VERSION 5.7 ;
  NOWIREEXTENSIONATPIN ON ;
  DIVIDERCHAR "/" ;
  BUSBITCHARS "[]" ;
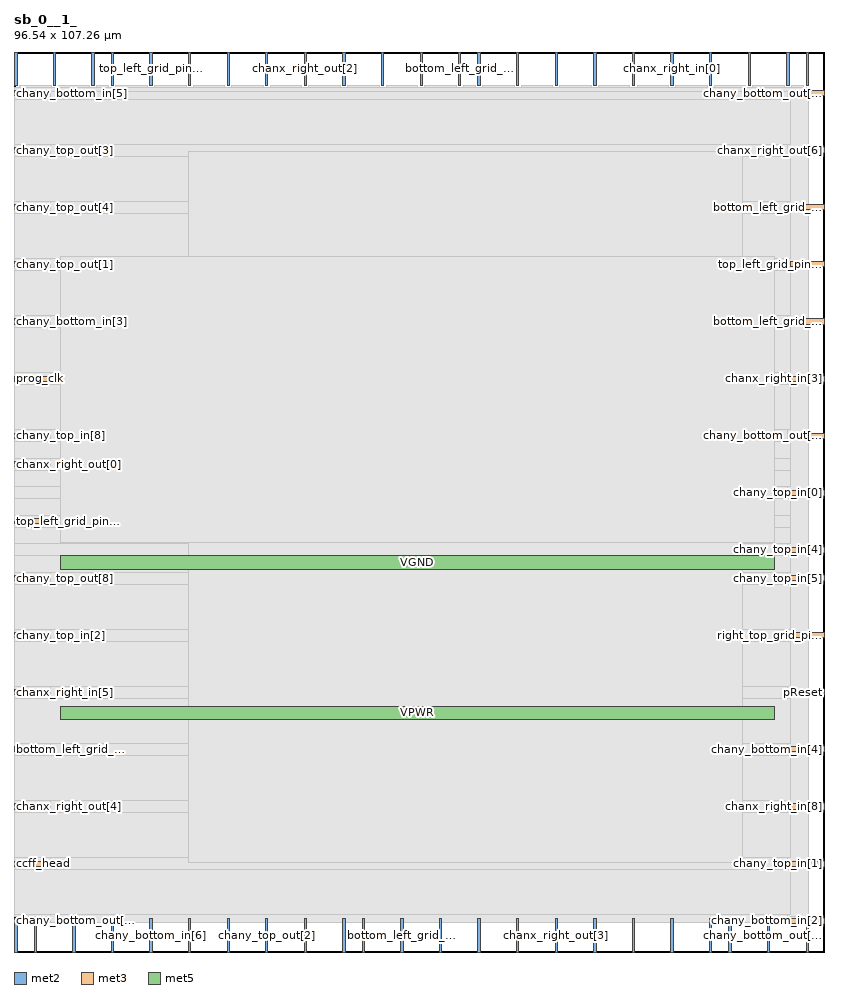
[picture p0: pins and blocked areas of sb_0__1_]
MACRO sb_0__1_
  CLASS BLOCK ;
  FOREIGN sb_0__1_ ;
  ORIGIN 0.000 0.000 ;
  SIZE 96.540 BY 107.260 ;
  PIN bottom_left_grid_pin_11_
    DIRECTION INPUT ;
    PORT
      LAYER met2 ;
        RECT 52.990 103.260 53.270 107.260 ;
    END
  END bottom_left_grid_pin_11_
  PIN bottom_left_grid_pin_13_
    DIRECTION INPUT ;
    PORT
      LAYER met2 ;
        RECT 92.090 103.260 92.370 107.260 ;
    END
  END bottom_left_grid_pin_13_
  PIN bottom_left_grid_pin_15_
    DIRECTION INPUT ;
    PORT
      LAYER met3 ;
        RECT 0.000 23.840 4.000 24.440 ;
    END
  END bottom_left_grid_pin_15_
  PIN bottom_left_grid_pin_1_
    DIRECTION INPUT ;
    PORT
      LAYER met2 ;
        RECT 9.290 103.260 9.570 107.260 ;
    END
  END bottom_left_grid_pin_1_
  PIN bottom_left_grid_pin_3_
    DIRECTION INPUT ;
    PORT
      LAYER met3 ;
        RECT 92.540 74.840 96.540 75.440 ;
    END
  END bottom_left_grid_pin_3_
  PIN bottom_left_grid_pin_5_
    DIRECTION INPUT ;
    PORT
      LAYER met2 ;
        RECT 39.190 0.000 39.470 4.000 ;
    END
  END bottom_left_grid_pin_5_
  PIN bottom_left_grid_pin_7_
    DIRECTION INPUT ;
    PORT
      LAYER met2 ;
        RECT 46.090 0.000 46.370 4.000 ;
    END
  END bottom_left_grid_pin_7_
  PIN bottom_left_grid_pin_9_
    DIRECTION INPUT ;
    PORT
      LAYER met3 ;
        RECT 92.540 88.440 96.540 89.040 ;
    END
  END bottom_left_grid_pin_9_
  PIN bottom_right_grid_pin_11_
    DIRECTION INPUT ;
    PORT
      LAYER met2 ;
        RECT 55.290 103.260 55.570 107.260 ;
    END
  END bottom_right_grid_pin_11_
  PIN ccff_head
    DIRECTION INPUT ;
    PORT
      LAYER met3 ;
        RECT 0.000 10.240 4.000 10.840 ;
    END
  END ccff_head
  PIN ccff_tail
    DIRECTION OUTPUT TRISTATE ;
    PORT
      LAYER met2 ;
        RECT 94.390 0.000 94.670 4.000 ;
    END
  END ccff_tail
  PIN chanx_right_in[0]
    DIRECTION INPUT ;
    PORT
      LAYER met2 ;
        RECT 78.290 103.260 78.570 107.260 ;
    END
  END chanx_right_in[0]
  PIN chanx_right_in[1]
    DIRECTION INPUT ;
    PORT
      LAYER met2 ;
        RECT 50.690 0.000 50.970 4.000 ;
    END
  END chanx_right_in[1]
  PIN chanx_right_in[2]
    DIRECTION INPUT ;
    PORT
      LAYER met2 ;
        RECT 29.990 103.260 30.270 107.260 ;
    END
  END chanx_right_in[2]
  PIN chanx_right_in[3]
    DIRECTION INPUT ;
    PORT
      LAYER met3 ;
        RECT 92.540 68.040 96.540 68.640 ;
    END
  END chanx_right_in[3]
  PIN chanx_right_in[4]
    DIRECTION INPUT ;
    PORT
      LAYER met2 ;
        RECT 6.990 0.000 7.270 4.000 ;
    END
  END chanx_right_in[4]
  PIN chanx_right_in[5]
    DIRECTION INPUT ;
    PORT
      LAYER met3 ;
        RECT 0.000 30.640 4.000 31.240 ;
    END
  END chanx_right_in[5]
  PIN chanx_right_in[6]
    DIRECTION INPUT ;
    PORT
      LAYER met2 ;
        RECT 59.890 103.260 60.170 107.260 ;
    END
  END chanx_right_in[6]
  PIN chanx_right_in[7]
    DIRECTION INPUT ;
    PORT
      LAYER met2 ;
        RECT 82.890 0.000 83.170 4.000 ;
    END
  END chanx_right_in[7]
  PIN chanx_right_in[8]
    DIRECTION INPUT ;
    PORT
      LAYER met3 ;
        RECT 92.540 17.040 96.540 17.640 ;
    END
  END chanx_right_in[8]
  PIN chanx_right_out[0]
    DIRECTION OUTPUT TRISTATE ;
    PORT
      LAYER met3 ;
        RECT 0.000 57.840 4.000 58.440 ;
    END
  END chanx_right_out[0]
  PIN chanx_right_out[1]
    DIRECTION OUTPUT TRISTATE ;
    PORT
      LAYER met2 ;
        RECT 94.390 103.260 94.670 107.260 ;
    END
  END chanx_right_out[1]
  PIN chanx_right_out[2]
    DIRECTION OUTPUT TRISTATE ;
    PORT
      LAYER met2 ;
        RECT 34.590 103.260 34.870 107.260 ;
    END
  END chanx_right_out[2]
  PIN chanx_right_out[3]
    DIRECTION OUTPUT TRISTATE ;
    PORT
      LAYER met2 ;
        RECT 64.490 0.000 64.770 4.000 ;
    END
  END chanx_right_out[3]
  PIN chanx_right_out[4]
    DIRECTION OUTPUT TRISTATE ;
    PORT
      LAYER met3 ;
        RECT 0.000 17.040 4.000 17.640 ;
    END
  END chanx_right_out[4]
  PIN chanx_right_out[5]
    DIRECTION OUTPUT TRISTATE ;
    PORT
      LAYER met2 ;
        RECT 20.790 0.000 21.070 4.000 ;
    END
  END chanx_right_out[5]
  PIN chanx_right_out[6]
    DIRECTION OUTPUT TRISTATE ;
    PORT
      LAYER met3 ;
        RECT 92.540 95.240 96.540 95.840 ;
    END
  END chanx_right_out[6]
  PIN chanx_right_out[7]
    DIRECTION OUTPUT TRISTATE ;
    PORT
      LAYER met2 ;
        RECT 0.090 103.260 0.370 107.260 ;
    END
  END chanx_right_out[7]
  PIN chanx_right_out[8]
    DIRECTION OUTPUT TRISTATE ;
    PORT
      LAYER met2 ;
        RECT 4.690 103.260 4.970 107.260 ;
    END
  END chanx_right_out[8]
  PIN chany_bottom_in[0]
    DIRECTION INPUT ;
    PORT
      LAYER met2 ;
        RECT 73.690 103.260 73.970 107.260 ;
    END
  END chany_bottom_in[0]
  PIN chany_bottom_in[1]
    DIRECTION INPUT ;
    PORT
      LAYER met2 ;
        RECT 11.590 103.260 11.870 107.260 ;
    END
  END chany_bottom_in[1]
  PIN chany_bottom_in[2]
    DIRECTION INPUT ;
    PORT
      LAYER met3 ;
        RECT 92.540 3.440 96.540 4.040 ;
    END
  END chany_bottom_in[2]
  PIN chany_bottom_in[3]
    DIRECTION INPUT ;
    PORT
      LAYER met3 ;
        RECT 0.000 74.840 4.000 75.440 ;
    END
  END chany_bottom_in[3]
  PIN chany_bottom_in[4]
    DIRECTION INPUT ;
    PORT
      LAYER met3 ;
        RECT 92.540 23.840 96.540 24.440 ;
    END
  END chany_bottom_in[4]
  PIN chany_bottom_in[5]
    DIRECTION INPUT ;
    PORT
      LAYER met3 ;
        RECT 0.000 102.040 4.000 102.640 ;
    END
  END chany_bottom_in[5]
  PIN chany_bottom_in[6]
    DIRECTION INPUT ;
    PORT
      LAYER met2 ;
        RECT 16.190 0.000 16.470 4.000 ;
    END
  END chany_bottom_in[6]
  PIN chany_bottom_in[7]
    DIRECTION INPUT ;
    PORT
      LAYER met2 ;
        RECT 11.590 0.000 11.870 4.000 ;
    END
  END chany_bottom_in[7]
  PIN chany_bottom_in[8]
    DIRECTION INPUT ;
    PORT
      LAYER met2 ;
        RECT 55.290 0.000 55.570 4.000 ;
    END
  END chany_bottom_in[8]
  PIN chany_bottom_out[0]
    DIRECTION OUTPUT TRISTATE ;
    PORT
      LAYER met3 ;
        RECT 0.000 3.440 4.000 4.040 ;
    END
  END chany_bottom_out[0]
  PIN chany_bottom_out[1]
    DIRECTION OUTPUT TRISTATE ;
    PORT
      LAYER met2 ;
        RECT 34.590 0.000 34.870 4.000 ;
    END
  END chany_bottom_out[1]
  PIN chany_bottom_out[2]
    DIRECTION OUTPUT TRISTATE ;
    PORT
      LAYER met2 ;
        RECT 25.390 0.000 25.670 4.000 ;
    END
  END chany_bottom_out[2]
  PIN chany_bottom_out[3]
    DIRECTION OUTPUT TRISTATE ;
    PORT
      LAYER met2 ;
        RECT 64.490 103.260 64.770 107.260 ;
    END
  END chany_bottom_out[3]
  PIN chany_bottom_out[4]
    DIRECTION OUTPUT TRISTATE ;
    PORT
      LAYER met2 ;
        RECT 2.390 0.000 2.670 4.000 ;
    END
  END chany_bottom_out[4]
  PIN chany_bottom_out[5]
    DIRECTION OUTPUT TRISTATE ;
    PORT
      LAYER met3 ;
        RECT 92.540 61.240 96.540 61.840 ;
    END
  END chany_bottom_out[5]
  PIN chany_bottom_out[6]
    DIRECTION OUTPUT TRISTATE ;
    PORT
      LAYER met2 ;
        RECT 89.790 0.000 90.070 4.000 ;
    END
  END chany_bottom_out[6]
  PIN chany_bottom_out[7]
    DIRECTION OUTPUT TRISTATE ;
    PORT
      LAYER met2 ;
        RECT 48.390 103.260 48.670 107.260 ;
    END
  END chany_bottom_out[7]
  PIN chany_bottom_out[8]
    DIRECTION OUTPUT TRISTATE ;
    PORT
      LAYER met3 ;
        RECT 92.540 102.040 96.540 102.640 ;
    END
  END chany_bottom_out[8]
  PIN chany_top_in[0]
    DIRECTION INPUT ;
    PORT
      LAYER met3 ;
        RECT 92.540 54.440 96.540 55.040 ;
    END
  END chany_top_in[0]
  PIN chany_top_in[1]
    DIRECTION INPUT ;
    PORT
      LAYER met3 ;
        RECT 92.540 10.240 96.540 10.840 ;
    END
  END chany_top_in[1]
  PIN chany_top_in[2]
    DIRECTION INPUT ;
    PORT
      LAYER met3 ;
        RECT 0.000 37.440 4.000 38.040 ;
    END
  END chany_top_in[2]
  PIN chany_top_in[3]
    DIRECTION INPUT ;
    PORT
      LAYER met2 ;
        RECT 20.790 103.260 21.070 107.260 ;
    END
  END chany_top_in[3]
  PIN chany_top_in[4]
    DIRECTION INPUT ;
    PORT
      LAYER met3 ;
        RECT 92.540 47.640 96.540 48.240 ;
    END
  END chany_top_in[4]
  PIN chany_top_in[5]
    DIRECTION INPUT ;
    PORT
      LAYER met3 ;
        RECT 92.540 44.240 96.540 44.840 ;
    END
  END chany_top_in[5]
  PIN chany_top_in[6]
    DIRECTION INPUT ;
    PORT
      LAYER met2 ;
        RECT 43.790 103.260 44.070 107.260 ;
    END
  END chany_top_in[6]
  PIN chany_top_in[7]
    DIRECTION INPUT ;
    PORT
      LAYER met2 ;
        RECT 87.490 103.260 87.770 107.260 ;
    END
  END chany_top_in[7]
  PIN chany_top_in[8]
    DIRECTION INPUT ;
    PORT
      LAYER met3 ;
        RECT 0.000 61.240 4.000 61.840 ;
    END
  END chany_top_in[8]
  PIN chany_top_out[0]
    DIRECTION OUTPUT TRISTATE ;
    PORT
      LAYER met2 ;
        RECT 0.090 0.000 0.370 4.000 ;
    END
  END chany_top_out[0]
  PIN chany_top_out[1]
    DIRECTION OUTPUT TRISTATE ;
    PORT
      LAYER met3 ;
        RECT 0.000 81.640 4.000 82.240 ;
    END
  END chany_top_out[1]
  PIN chany_top_out[2]
    DIRECTION OUTPUT TRISTATE ;
    PORT
      LAYER met2 ;
        RECT 29.990 0.000 30.270 4.000 ;
    END
  END chany_top_out[2]
  PIN chany_top_out[3]
    DIRECTION OUTPUT TRISTATE ;
    PORT
      LAYER met3 ;
        RECT 0.000 95.240 4.000 95.840 ;
    END
  END chany_top_out[3]
  PIN chany_top_out[4]
    DIRECTION OUTPUT TRISTATE ;
    PORT
      LAYER met3 ;
        RECT 0.000 88.440 4.000 89.040 ;
    END
  END chany_top_out[4]
  PIN chany_top_out[5]
    DIRECTION OUTPUT TRISTATE ;
    PORT
      LAYER met2 ;
        RECT 59.890 0.000 60.170 4.000 ;
    END
  END chany_top_out[5]
  PIN chany_top_out[6]
    DIRECTION OUTPUT TRISTATE ;
    PORT
      LAYER met2 ;
        RECT 78.290 0.000 78.570 4.000 ;
    END
  END chany_top_out[6]
  PIN chany_top_out[7]
    DIRECTION OUTPUT TRISTATE ;
    PORT
      LAYER met2 ;
        RECT 69.090 103.260 69.370 107.260 ;
    END
  END chany_top_out[7]
  PIN chany_top_out[8]
    DIRECTION OUTPUT TRISTATE ;
    PORT
      LAYER met3 ;
        RECT 0.000 44.240 4.000 44.840 ;
    END
  END chany_top_out[8]
  PIN pReset
    DIRECTION INPUT ;
    PORT
      LAYER met3 ;
        RECT 92.540 30.640 96.540 31.240 ;
    END
  END pReset
  PIN prog_clk
    DIRECTION INPUT ;
    PORT
      LAYER met3 ;
        RECT 0.000 68.040 4.000 68.640 ;
    END
  END prog_clk
  PIN right_bottom_grid_pin_12_
    DIRECTION INPUT ;
    PORT
      LAYER met2 ;
        RECT 39.190 103.260 39.470 107.260 ;
    END
  END right_bottom_grid_pin_12_
  PIN right_top_grid_pin_10_
    DIRECTION INPUT ;
    PORT
      LAYER met3 ;
        RECT 92.540 37.440 96.540 38.040 ;
    END
  END right_top_grid_pin_10_
  PIN top_left_grid_pin_11_
    DIRECTION INPUT ;
    PORT
      LAYER met3 ;
        RECT 0.000 51.040 4.000 51.640 ;
    END
  END top_left_grid_pin_11_
  PIN top_left_grid_pin_13_
    DIRECTION INPUT ;
    PORT
      LAYER met2 ;
        RECT 69.090 0.000 69.370 4.000 ;
    END
  END top_left_grid_pin_13_
  PIN top_left_grid_pin_15_
    DIRECTION INPUT ;
    PORT
      LAYER met2 ;
        RECT 25.390 103.260 25.670 107.260 ;
    END
  END top_left_grid_pin_15_
  PIN top_left_grid_pin_1_
    DIRECTION INPUT ;
    PORT
      LAYER met2 ;
        RECT 85.190 0.000 85.470 4.000 ;
    END
  END top_left_grid_pin_1_
  PIN top_left_grid_pin_3_
    DIRECTION INPUT ;
    PORT
      LAYER met2 ;
        RECT 73.690 0.000 73.970 4.000 ;
    END
  END top_left_grid_pin_3_
  PIN top_left_grid_pin_5_
    DIRECTION INPUT ;
    PORT
      LAYER met2 ;
        RECT 82.890 103.260 83.170 107.260 ;
    END
  END top_left_grid_pin_5_
  PIN top_left_grid_pin_7_
    DIRECTION INPUT ;
    PORT
      LAYER met3 ;
        RECT 92.540 81.640 96.540 82.240 ;
    END
  END top_left_grid_pin_7_
  PIN top_left_grid_pin_9_
    DIRECTION INPUT ;
    PORT
      LAYER met2 ;
        RECT 16.190 103.260 16.470 107.260 ;
    END
  END top_left_grid_pin_9_
  PIN top_right_grid_pin_11_
    DIRECTION INPUT ;
    PORT
      LAYER met2 ;
        RECT 41.490 0.000 41.770 4.000 ;
    END
  END top_right_grid_pin_11_
  PIN VPWR
    DIRECTION INPUT ;
    USE POWER ;
    PORT
      LAYER met5 ;
        RECT 5.520 27.715 90.620 29.315 ;
    END
  END VPWR
  PIN VGND
    DIRECTION INPUT ;
    USE GROUND ;
    PORT
      LAYER met5 ;
        RECT 5.520 45.595 90.620 47.195 ;
    END
  END VGND
  OBS
      LAYER li1 ;
        RECT 5.520 10.795 90.620 95.285 ;
      LAYER met1 ;
        RECT 0.070 10.640 94.690 95.440 ;
      LAYER met2 ;
        RECT 0.650 102.980 4.410 103.260 ;
        RECT 5.250 102.980 9.010 103.260 ;
        RECT 9.850 102.980 11.310 103.260 ;
        RECT 12.150 102.980 15.910 103.260 ;
        RECT 16.750 102.980 20.510 103.260 ;
        RECT 21.350 102.980 25.110 103.260 ;
        RECT 25.950 102.980 29.710 103.260 ;
        RECT 30.550 102.980 34.310 103.260 ;
        RECT 35.150 102.980 38.910 103.260 ;
        RECT 39.750 102.980 43.510 103.260 ;
        RECT 44.350 102.980 48.110 103.260 ;
        RECT 48.950 102.980 52.710 103.260 ;
        RECT 53.550 102.980 55.010 103.260 ;
        RECT 55.850 102.980 59.610 103.260 ;
        RECT 60.450 102.980 64.210 103.260 ;
        RECT 65.050 102.980 68.810 103.260 ;
        RECT 69.650 102.980 73.410 103.260 ;
        RECT 74.250 102.980 78.010 103.260 ;
        RECT 78.850 102.980 82.610 103.260 ;
        RECT 83.450 102.980 87.210 103.260 ;
        RECT 88.050 102.980 91.810 103.260 ;
        RECT 92.650 102.980 94.110 103.260 ;
        RECT 0.090 4.280 94.660 102.980 ;
        RECT 0.650 3.555 2.110 4.280 ;
        RECT 2.950 3.555 6.710 4.280 ;
        RECT 7.550 3.555 11.310 4.280 ;
        RECT 12.150 3.555 15.910 4.280 ;
        RECT 16.750 3.555 20.510 4.280 ;
        RECT 21.350 3.555 25.110 4.280 ;
        RECT 25.950 3.555 29.710 4.280 ;
        RECT 30.550 3.555 34.310 4.280 ;
        RECT 35.150 3.555 38.910 4.280 ;
        RECT 39.750 3.555 41.210 4.280 ;
        RECT 42.050 3.555 45.810 4.280 ;
        RECT 46.650 3.555 50.410 4.280 ;
        RECT 51.250 3.555 55.010 4.280 ;
        RECT 55.850 3.555 59.610 4.280 ;
        RECT 60.450 3.555 64.210 4.280 ;
        RECT 65.050 3.555 68.810 4.280 ;
        RECT 69.650 3.555 73.410 4.280 ;
        RECT 74.250 3.555 78.010 4.280 ;
        RECT 78.850 3.555 82.610 4.280 ;
        RECT 83.450 3.555 84.910 4.280 ;
        RECT 85.750 3.555 89.510 4.280 ;
        RECT 90.350 3.555 94.110 4.280 ;
      LAYER met3 ;
        RECT 4.400 101.640 92.140 102.505 ;
        RECT 0.065 96.240 92.540 101.640 ;
        RECT 4.400 94.840 92.140 96.240 ;
        RECT 0.065 89.440 92.540 94.840 ;
        RECT 4.400 88.040 92.140 89.440 ;
        RECT 0.065 82.640 92.540 88.040 ;
        RECT 4.400 81.240 92.140 82.640 ;
        RECT 0.065 75.840 92.540 81.240 ;
        RECT 4.400 74.440 92.140 75.840 ;
        RECT 0.065 69.040 92.540 74.440 ;
        RECT 4.400 67.640 92.140 69.040 ;
        RECT 0.065 62.240 92.540 67.640 ;
        RECT 4.400 60.840 92.140 62.240 ;
        RECT 0.065 58.840 92.540 60.840 ;
        RECT 4.400 57.440 92.540 58.840 ;
        RECT 0.065 55.440 92.540 57.440 ;
        RECT 0.065 54.040 92.140 55.440 ;
        RECT 0.065 52.040 92.540 54.040 ;
        RECT 4.400 50.640 92.540 52.040 ;
        RECT 0.065 48.640 92.540 50.640 ;
        RECT 0.065 47.240 92.140 48.640 ;
        RECT 0.065 45.240 92.540 47.240 ;
        RECT 4.400 43.840 92.140 45.240 ;
        RECT 0.065 38.440 92.540 43.840 ;
        RECT 4.400 37.040 92.140 38.440 ;
        RECT 0.065 31.640 92.540 37.040 ;
        RECT 4.400 30.240 92.140 31.640 ;
        RECT 0.065 24.840 92.540 30.240 ;
        RECT 4.400 23.440 92.140 24.840 ;
        RECT 0.065 18.040 92.540 23.440 ;
        RECT 4.400 16.640 92.140 18.040 ;
        RECT 0.065 11.240 92.540 16.640 ;
        RECT 4.400 9.840 92.140 11.240 ;
        RECT 0.065 4.440 92.540 9.840 ;
        RECT 4.400 3.575 92.140 4.440 ;
      LAYER met4 ;
        RECT 20.810 10.640 86.770 95.440 ;
      LAYER met5 ;
        RECT 5.520 48.795 90.620 82.945 ;
  END
END sb_0__1_
END LIBRARY

